VERSION 5.7 ;
  NOWIREEXTENSIONATPIN ON ;
  DIVIDERCHAR "/" ;
  BUSBITCHARS "[]" ;
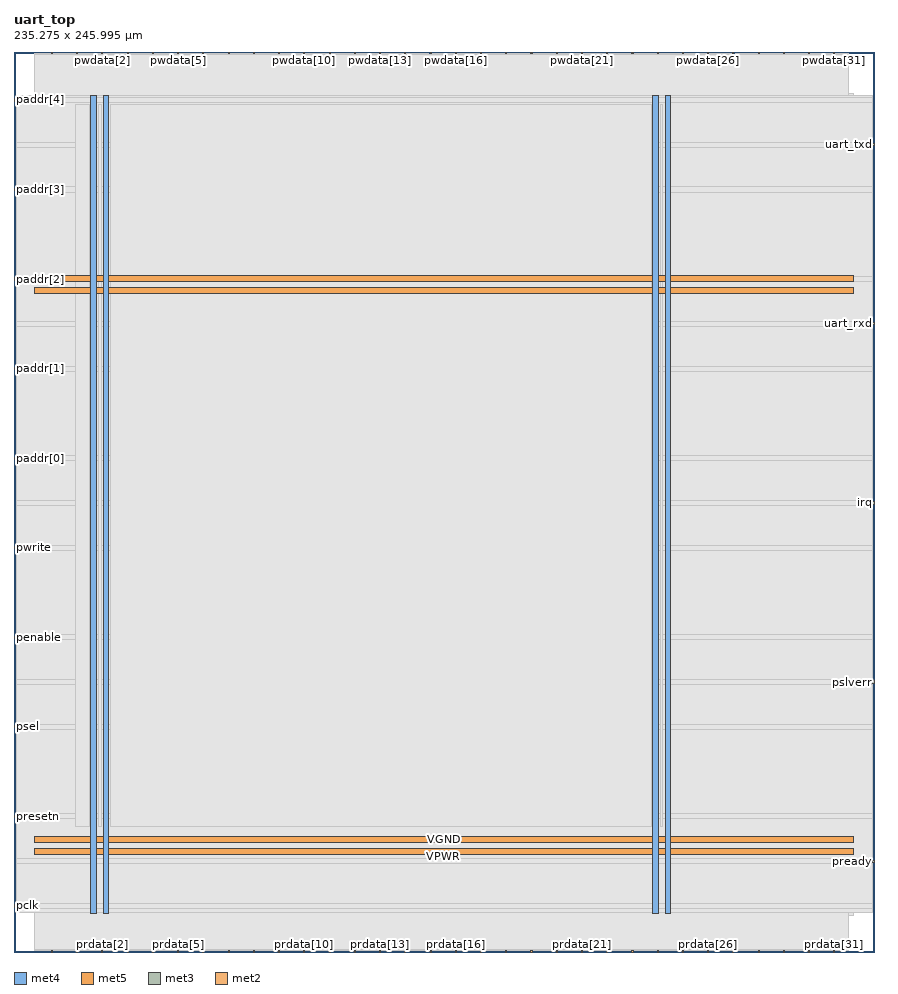
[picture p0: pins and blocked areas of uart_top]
MACRO uart_top
  CLASS BLOCK ;
  FOREIGN uart_top ;
  ORIGIN 0.000 0.000 ;
  SIZE 235.275 BY 245.995 ;
  PIN VGND
    DIRECTION INOUT ;
    USE GROUND ;
    PORT
      LAYER met4 ;
        RECT 24.340 10.640 25.940 234.160 ;
    END
    PORT
      LAYER met4 ;
        RECT 177.940 10.640 179.540 234.160 ;
    END
    PORT
      LAYER met5 ;
        RECT 5.520 30.030 229.540 31.630 ;
    END
    PORT
      LAYER met5 ;
        RECT 5.520 183.210 229.540 184.810 ;
    END
  END VGND
  PIN VPWR
    DIRECTION INOUT ;
    USE POWER ;
    PORT
      LAYER met4 ;
        RECT 21.040 10.640 22.640 234.160 ;
    END
    PORT
      LAYER met4 ;
        RECT 174.640 10.640 176.240 234.160 ;
    END
    PORT
      LAYER met5 ;
        RECT 5.520 26.730 229.540 28.330 ;
    END
    PORT
      LAYER met5 ;
        RECT 5.520 179.910 229.540 181.510 ;
    END
  END VPWR
  PIN irq
    DIRECTION OUTPUT ;
    USE SIGNAL ;
    ANTENNADIFFAREA 0.702900 ;
    PORT
      LAYER met3 ;
        RECT 234.675 122.440 235.275 123.040 ;
    END
  END irq
  PIN paddr[0]
    DIRECTION INPUT ;
    USE SIGNAL ;
    PORT
      LAYER met3 ;
        RECT 0.000 134.680 0.600 135.280 ;
    END
  END paddr[0]
  PIN paddr[1]
    DIRECTION INPUT ;
    USE SIGNAL ;
    PORT
      LAYER met3 ;
        RECT 0.000 159.160 0.600 159.760 ;
    END
  END paddr[1]
  PIN paddr[2]
    DIRECTION INPUT ;
    USE SIGNAL ;
    ANTENNAGATEAREA 0.647700 ;
    ANTENNADIFFAREA 0.434700 ;
    PORT
      LAYER met3 ;
        RECT 0.000 183.640 0.600 184.240 ;
    END
  END paddr[2]
  PIN paddr[3]
    DIRECTION INPUT ;
    USE SIGNAL ;
    ANTENNAGATEAREA 0.647700 ;
    ANTENNADIFFAREA 0.434700 ;
    PORT
      LAYER met3 ;
        RECT 0.000 208.120 0.600 208.720 ;
    END
  END paddr[3]
  PIN paddr[4]
    DIRECTION INPUT ;
    USE SIGNAL ;
    ANTENNAGATEAREA 0.647700 ;
    ANTENNADIFFAREA 0.434700 ;
    PORT
      LAYER met3 ;
        RECT 0.000 232.600 0.600 233.200 ;
    END
  END paddr[4]
  PIN pclk
    DIRECTION INPUT ;
    USE SIGNAL ;
    ANTENNAGATEAREA 1.286700 ;
    ANTENNADIFFAREA 0.434700 ;
    PORT
      LAYER met3 ;
        RECT 0.000 12.280 0.600 12.880 ;
    END
  END pclk
  PIN penable
    DIRECTION INPUT ;
    USE SIGNAL ;
    ANTENNAGATEAREA 0.647700 ;
    ANTENNADIFFAREA 0.434700 ;
    PORT
      LAYER met3 ;
        RECT 0.000 85.720 0.600 86.320 ;
    END
  END penable
  PIN prdata[0]
    DIRECTION OUTPUT ;
    USE SIGNAL ;
    ANTENNADIFFAREA 0.702900 ;
    PORT
      LAYER met2 ;
        RECT 10.210 0.000 10.490 0.280 ;
    END
  END prdata[0]
  PIN prdata[10]
    DIRECTION OUTPUT ;
    USE SIGNAL ;
    ANTENNADIFFAREA 0.702900 ;
    PORT
      LAYER met2 ;
        RECT 79.210 0.000 79.490 0.280 ;
    END
  END prdata[10]
  PIN prdata[11]
    DIRECTION OUTPUT ;
    USE SIGNAL ;
    ANTENNADIFFAREA 0.702900 ;
    PORT
      LAYER met2 ;
        RECT 86.110 0.000 86.390 0.280 ;
    END
  END prdata[11]
  PIN prdata[12]
    DIRECTION OUTPUT ;
    USE SIGNAL ;
    ANTENNADIFFAREA 0.702900 ;
    PORT
      LAYER met2 ;
        RECT 93.010 0.000 93.290 0.280 ;
    END
  END prdata[12]
  PIN prdata[13]
    DIRECTION OUTPUT ;
    USE SIGNAL ;
    ANTENNADIFFAREA 0.702900 ;
    PORT
      LAYER met2 ;
        RECT 99.910 0.000 100.190 0.280 ;
    END
  END prdata[13]
  PIN prdata[14]
    DIRECTION OUTPUT ;
    USE SIGNAL ;
    ANTENNADIFFAREA 0.702900 ;
    PORT
      LAYER met2 ;
        RECT 106.810 0.000 107.090 0.280 ;
    END
  END prdata[14]
  PIN prdata[15]
    DIRECTION OUTPUT ;
    USE SIGNAL ;
    ANTENNADIFFAREA 0.702900 ;
    PORT
      LAYER met2 ;
        RECT 113.710 0.000 113.990 0.280 ;
    END
  END prdata[15]
  PIN prdata[16]
    DIRECTION OUTPUT ;
    USE SIGNAL ;
    ANTENNADIFFAREA 0.702900 ;
    PORT
      LAYER met2 ;
        RECT 120.610 0.000 120.890 0.280 ;
    END
  END prdata[16]
  PIN prdata[17]
    DIRECTION OUTPUT ;
    USE SIGNAL ;
    ANTENNADIFFAREA 0.702900 ;
    PORT
      LAYER met2 ;
        RECT 127.510 0.000 127.790 0.280 ;
    END
  END prdata[17]
  PIN prdata[18]
    DIRECTION OUTPUT ;
    USE SIGNAL ;
    ANTENNADIFFAREA 0.702900 ;
    PORT
      LAYER met2 ;
        RECT 134.410 0.000 134.690 0.280 ;
    END
  END prdata[18]
  PIN prdata[19]
    DIRECTION OUTPUT ;
    USE SIGNAL ;
    ANTENNADIFFAREA 0.702900 ;
    PORT
      LAYER met2 ;
        RECT 141.310 0.000 141.590 0.280 ;
    END
  END prdata[19]
  PIN prdata[1]
    DIRECTION OUTPUT ;
    USE SIGNAL ;
    ANTENNADIFFAREA 0.702900 ;
    PORT
      LAYER met2 ;
        RECT 17.110 0.000 17.390 0.280 ;
    END
  END prdata[1]
  PIN prdata[20]
    DIRECTION OUTPUT ;
    USE SIGNAL ;
    ANTENNADIFFAREA 0.702900 ;
    PORT
      LAYER met2 ;
        RECT 148.210 0.000 148.490 0.280 ;
    END
  END prdata[20]
  PIN prdata[21]
    DIRECTION OUTPUT ;
    USE SIGNAL ;
    PORT
      LAYER met2 ;
        RECT 155.110 0.000 155.390 0.280 ;
    END
  END prdata[21]
  PIN prdata[22]
    DIRECTION OUTPUT ;
    USE SIGNAL ;
    PORT
      LAYER met2 ;
        RECT 162.010 0.000 162.290 0.280 ;
    END
  END prdata[22]
  PIN prdata[23]
    DIRECTION OUTPUT ;
    USE SIGNAL ;
    PORT
      LAYER met2 ;
        RECT 168.910 0.000 169.190 0.280 ;
    END
  END prdata[23]
  PIN prdata[24]
    DIRECTION OUTPUT ;
    USE SIGNAL ;
    PORT
      LAYER met2 ;
        RECT 175.810 0.000 176.090 0.280 ;
    END
  END prdata[24]
  PIN prdata[25]
    DIRECTION OUTPUT ;
    USE SIGNAL ;
    PORT
      LAYER met2 ;
        RECT 182.710 0.000 182.990 0.280 ;
    END
  END prdata[25]
  PIN prdata[26]
    DIRECTION OUTPUT ;
    USE SIGNAL ;
    PORT
      LAYER met2 ;
        RECT 189.610 0.000 189.890 0.280 ;
    END
  END prdata[26]
  PIN prdata[27]
    DIRECTION OUTPUT ;
    USE SIGNAL ;
    PORT
      LAYER met2 ;
        RECT 196.510 0.000 196.790 0.280 ;
    END
  END prdata[27]
  PIN prdata[28]
    DIRECTION OUTPUT ;
    USE SIGNAL ;
    PORT
      LAYER met2 ;
        RECT 203.410 0.000 203.690 0.280 ;
    END
  END prdata[28]
  PIN prdata[29]
    DIRECTION OUTPUT ;
    USE SIGNAL ;
    PORT
      LAYER met2 ;
        RECT 210.310 0.000 210.590 0.280 ;
    END
  END prdata[29]
  PIN prdata[2]
    DIRECTION OUTPUT ;
    USE SIGNAL ;
    ANTENNADIFFAREA 0.702900 ;
    PORT
      LAYER met2 ;
        RECT 24.010 0.000 24.290 0.280 ;
    END
  END prdata[2]
  PIN prdata[30]
    DIRECTION OUTPUT ;
    USE SIGNAL ;
    PORT
      LAYER met2 ;
        RECT 217.210 0.000 217.490 0.280 ;
    END
  END prdata[30]
  PIN prdata[31]
    DIRECTION OUTPUT ;
    USE SIGNAL ;
    PORT
      LAYER met2 ;
        RECT 224.110 0.000 224.390 0.280 ;
    END
  END prdata[31]
  PIN prdata[3]
    DIRECTION OUTPUT ;
    USE SIGNAL ;
    ANTENNADIFFAREA 0.702900 ;
    PORT
      LAYER met2 ;
        RECT 30.910 0.000 31.190 0.280 ;
    END
  END prdata[3]
  PIN prdata[4]
    DIRECTION OUTPUT ;
    USE SIGNAL ;
    ANTENNADIFFAREA 0.702900 ;
    PORT
      LAYER met2 ;
        RECT 37.810 0.000 38.090 0.280 ;
    END
  END prdata[4]
  PIN prdata[5]
    DIRECTION OUTPUT ;
    USE SIGNAL ;
    ANTENNADIFFAREA 0.702900 ;
    PORT
      LAYER met2 ;
        RECT 44.710 0.000 44.990 0.280 ;
    END
  END prdata[5]
  PIN prdata[6]
    DIRECTION OUTPUT ;
    USE SIGNAL ;
    ANTENNADIFFAREA 0.702900 ;
    PORT
      LAYER met2 ;
        RECT 51.610 0.000 51.890 0.280 ;
    END
  END prdata[6]
  PIN prdata[7]
    DIRECTION OUTPUT ;
    USE SIGNAL ;
    ANTENNADIFFAREA 0.702900 ;
    PORT
      LAYER met2 ;
        RECT 58.510 0.000 58.790 0.280 ;
    END
  END prdata[7]
  PIN prdata[8]
    DIRECTION OUTPUT ;
    USE SIGNAL ;
    ANTENNADIFFAREA 0.702900 ;
    PORT
      LAYER met2 ;
        RECT 65.410 0.000 65.690 0.280 ;
    END
  END prdata[8]
  PIN prdata[9]
    DIRECTION OUTPUT ;
    USE SIGNAL ;
    ANTENNADIFFAREA 0.702900 ;
    PORT
      LAYER met2 ;
        RECT 72.310 0.000 72.590 0.280 ;
    END
  END prdata[9]
  PIN pready
    DIRECTION OUTPUT ;
    USE SIGNAL ;
    PORT
      LAYER met3 ;
        RECT 234.675 24.520 235.275 25.120 ;
    END
  END pready
  PIN presetn
    DIRECTION INPUT ;
    USE SIGNAL ;
    ANTENNAGATEAREA 1.177200 ;
    ANTENNADIFFAREA 0.434700 ;
    PORT
      LAYER met3 ;
        RECT 0.000 36.760 0.600 37.360 ;
    END
  END presetn
  PIN psel
    DIRECTION INPUT ;
    USE SIGNAL ;
    ANTENNAGATEAREA 0.647700 ;
    ANTENNADIFFAREA 0.434700 ;
    PORT
      LAYER met3 ;
        RECT 0.000 61.240 0.600 61.840 ;
    END
  END psel
  PIN pslverr
    DIRECTION OUTPUT ;
    USE SIGNAL ;
    ANTENNADIFFAREA 0.702900 ;
    PORT
      LAYER met3 ;
        RECT 234.675 73.480 235.275 74.080 ;
    END
  END pslverr
  PIN pwdata[0]
    DIRECTION INPUT ;
    USE SIGNAL ;
    ANTENNAGATEAREA 0.647700 ;
    ANTENNADIFFAREA 0.434700 ;
    PORT
      LAYER met2 ;
        RECT 10.210 245.715 10.490 245.995 ;
    END
  END pwdata[0]
  PIN pwdata[10]
    DIRECTION INPUT ;
    USE SIGNAL ;
    ANTENNAGATEAREA 0.647700 ;
    ANTENNADIFFAREA 0.434700 ;
    PORT
      LAYER met2 ;
        RECT 79.210 245.715 79.490 245.995 ;
    END
  END pwdata[10]
  PIN pwdata[11]
    DIRECTION INPUT ;
    USE SIGNAL ;
    ANTENNAGATEAREA 0.647700 ;
    ANTENNADIFFAREA 0.434700 ;
    PORT
      LAYER met2 ;
        RECT 86.110 245.715 86.390 245.995 ;
    END
  END pwdata[11]
  PIN pwdata[12]
    DIRECTION INPUT ;
    USE SIGNAL ;
    ANTENNAGATEAREA 0.647700 ;
    ANTENNADIFFAREA 0.434700 ;
    PORT
      LAYER met2 ;
        RECT 93.010 245.715 93.290 245.995 ;
    END
  END pwdata[12]
  PIN pwdata[13]
    DIRECTION INPUT ;
    USE SIGNAL ;
    ANTENNAGATEAREA 0.647700 ;
    ANTENNADIFFAREA 0.434700 ;
    PORT
      LAYER met2 ;
        RECT 99.910 245.715 100.190 245.995 ;
    END
  END pwdata[13]
  PIN pwdata[14]
    DIRECTION INPUT ;
    USE SIGNAL ;
    ANTENNAGATEAREA 0.647700 ;
    ANTENNADIFFAREA 0.434700 ;
    PORT
      LAYER met2 ;
        RECT 106.810 245.715 107.090 245.995 ;
    END
  END pwdata[14]
  PIN pwdata[15]
    DIRECTION INPUT ;
    USE SIGNAL ;
    ANTENNAGATEAREA 0.647700 ;
    ANTENNADIFFAREA 0.434700 ;
    PORT
      LAYER met2 ;
        RECT 113.710 245.715 113.990 245.995 ;
    END
  END pwdata[15]
  PIN pwdata[16]
    DIRECTION INPUT ;
    USE SIGNAL ;
    PORT
      LAYER met2 ;
        RECT 120.610 245.715 120.890 245.995 ;
    END
  END pwdata[16]
  PIN pwdata[17]
    DIRECTION INPUT ;
    USE SIGNAL ;
    PORT
      LAYER met2 ;
        RECT 127.510 245.715 127.790 245.995 ;
    END
  END pwdata[17]
  PIN pwdata[18]
    DIRECTION INPUT ;
    USE SIGNAL ;
    PORT
      LAYER met2 ;
        RECT 134.410 245.715 134.690 245.995 ;
    END
  END pwdata[18]
  PIN pwdata[19]
    DIRECTION INPUT ;
    USE SIGNAL ;
    PORT
      LAYER met2 ;
        RECT 141.310 245.715 141.590 245.995 ;
    END
  END pwdata[19]
  PIN pwdata[1]
    DIRECTION INPUT ;
    USE SIGNAL ;
    ANTENNAGATEAREA 0.647700 ;
    ANTENNADIFFAREA 0.434700 ;
    PORT
      LAYER met2 ;
        RECT 17.110 245.715 17.390 245.995 ;
    END
  END pwdata[1]
  PIN pwdata[20]
    DIRECTION INPUT ;
    USE SIGNAL ;
    PORT
      LAYER met2 ;
        RECT 148.210 245.715 148.490 245.995 ;
    END
  END pwdata[20]
  PIN pwdata[21]
    DIRECTION INPUT ;
    USE SIGNAL ;
    PORT
      LAYER met2 ;
        RECT 155.110 245.715 155.390 245.995 ;
    END
  END pwdata[21]
  PIN pwdata[22]
    DIRECTION INPUT ;
    USE SIGNAL ;
    PORT
      LAYER met2 ;
        RECT 162.010 245.715 162.290 245.995 ;
    END
  END pwdata[22]
  PIN pwdata[23]
    DIRECTION INPUT ;
    USE SIGNAL ;
    PORT
      LAYER met2 ;
        RECT 168.910 245.715 169.190 245.995 ;
    END
  END pwdata[23]
  PIN pwdata[24]
    DIRECTION INPUT ;
    USE SIGNAL ;
    PORT
      LAYER met2 ;
        RECT 175.810 245.715 176.090 245.995 ;
    END
  END pwdata[24]
  PIN pwdata[25]
    DIRECTION INPUT ;
    USE SIGNAL ;
    PORT
      LAYER met2 ;
        RECT 182.710 245.715 182.990 245.995 ;
    END
  END pwdata[25]
  PIN pwdata[26]
    DIRECTION INPUT ;
    USE SIGNAL ;
    PORT
      LAYER met2 ;
        RECT 189.610 245.715 189.890 245.995 ;
    END
  END pwdata[26]
  PIN pwdata[27]
    DIRECTION INPUT ;
    USE SIGNAL ;
    PORT
      LAYER met2 ;
        RECT 196.510 245.715 196.790 245.995 ;
    END
  END pwdata[27]
  PIN pwdata[28]
    DIRECTION INPUT ;
    USE SIGNAL ;
    PORT
      LAYER met2 ;
        RECT 203.410 245.715 203.690 245.995 ;
    END
  END pwdata[28]
  PIN pwdata[29]
    DIRECTION INPUT ;
    USE SIGNAL ;
    PORT
      LAYER met2 ;
        RECT 210.310 245.715 210.590 245.995 ;
    END
  END pwdata[29]
  PIN pwdata[2]
    DIRECTION INPUT ;
    USE SIGNAL ;
    ANTENNAGATEAREA 0.647700 ;
    ANTENNADIFFAREA 0.434700 ;
    PORT
      LAYER met2 ;
        RECT 24.010 245.715 24.290 245.995 ;
    END
  END pwdata[2]
  PIN pwdata[30]
    DIRECTION INPUT ;
    USE SIGNAL ;
    PORT
      LAYER met2 ;
        RECT 217.210 245.715 217.490 245.995 ;
    END
  END pwdata[30]
  PIN pwdata[31]
    DIRECTION INPUT ;
    USE SIGNAL ;
    PORT
      LAYER met2 ;
        RECT 224.110 245.715 224.390 245.995 ;
    END
  END pwdata[31]
  PIN pwdata[3]
    DIRECTION INPUT ;
    USE SIGNAL ;
    ANTENNAGATEAREA 0.647700 ;
    ANTENNADIFFAREA 0.434700 ;
    PORT
      LAYER met2 ;
        RECT 30.910 245.715 31.190 245.995 ;
    END
  END pwdata[3]
  PIN pwdata[4]
    DIRECTION INPUT ;
    USE SIGNAL ;
    ANTENNAGATEAREA 0.631200 ;
    ANTENNADIFFAREA 0.434700 ;
    PORT
      LAYER met2 ;
        RECT 37.810 245.715 38.090 245.995 ;
    END
  END pwdata[4]
  PIN pwdata[5]
    DIRECTION INPUT ;
    USE SIGNAL ;
    ANTENNAGATEAREA 0.631200 ;
    ANTENNADIFFAREA 0.434700 ;
    PORT
      LAYER met2 ;
        RECT 44.710 245.715 44.990 245.995 ;
    END
  END pwdata[5]
  PIN pwdata[6]
    DIRECTION INPUT ;
    USE SIGNAL ;
    ANTENNAGATEAREA 0.647700 ;
    ANTENNADIFFAREA 0.434700 ;
    PORT
      LAYER met2 ;
        RECT 51.610 245.715 51.890 245.995 ;
    END
  END pwdata[6]
  PIN pwdata[7]
    DIRECTION INPUT ;
    USE SIGNAL ;
    ANTENNAGATEAREA 0.647700 ;
    ANTENNADIFFAREA 0.434700 ;
    PORT
      LAYER met2 ;
        RECT 58.510 245.715 58.790 245.995 ;
    END
  END pwdata[7]
  PIN pwdata[8]
    DIRECTION INPUT ;
    USE SIGNAL ;
    ANTENNAGATEAREA 0.647700 ;
    ANTENNADIFFAREA 0.434700 ;
    PORT
      LAYER met2 ;
        RECT 65.410 245.715 65.690 245.995 ;
    END
  END pwdata[8]
  PIN pwdata[9]
    DIRECTION INPUT ;
    USE SIGNAL ;
    ANTENNAGATEAREA 0.647700 ;
    ANTENNADIFFAREA 0.434700 ;
    PORT
      LAYER met2 ;
        RECT 72.310 245.715 72.590 245.995 ;
    END
  END pwdata[9]
  PIN pwrite
    DIRECTION INPUT ;
    USE SIGNAL ;
    ANTENNAGATEAREA 0.647700 ;
    ANTENNADIFFAREA 0.434700 ;
    PORT
      LAYER met3 ;
        RECT 0.000 110.200 0.600 110.800 ;
    END
  END pwrite
  PIN uart_rxd
    DIRECTION INPUT ;
    USE SIGNAL ;
    ANTENNAGATEAREA 0.647700 ;
    ANTENNADIFFAREA 0.434700 ;
    PORT
      LAYER met3 ;
        RECT 234.675 171.400 235.275 172.000 ;
    END
  END uart_rxd
  PIN uart_txd
    DIRECTION OUTPUT ;
    USE SIGNAL ;
    ANTENNADIFFAREA 0.702900 ;
    PORT
      LAYER met3 ;
        RECT 234.675 220.360 235.275 220.960 ;
    END
  END uart_txd
  OBS
      LAYER nwell ;
        RECT 5.330 10.795 229.730 234.005 ;
      LAYER li1 ;
        RECT 5.520 10.795 229.540 234.005 ;
      LAYER met1 ;
        RECT 5.520 9.900 229.540 234.560 ;
      LAYER met2 ;
        RECT 5.610 245.435 9.930 245.715 ;
        RECT 10.770 245.435 16.830 245.715 ;
        RECT 17.670 245.435 23.730 245.715 ;
        RECT 24.570 245.435 30.630 245.715 ;
        RECT 31.470 245.435 37.530 245.715 ;
        RECT 38.370 245.435 44.430 245.715 ;
        RECT 45.270 245.435 51.330 245.715 ;
        RECT 52.170 245.435 58.230 245.715 ;
        RECT 59.070 245.435 65.130 245.715 ;
        RECT 65.970 245.435 72.030 245.715 ;
        RECT 72.870 245.435 78.930 245.715 ;
        RECT 79.770 245.435 85.830 245.715 ;
        RECT 86.670 245.435 92.730 245.715 ;
        RECT 93.570 245.435 99.630 245.715 ;
        RECT 100.470 245.435 106.530 245.715 ;
        RECT 107.370 245.435 113.430 245.715 ;
        RECT 114.270 245.435 120.330 245.715 ;
        RECT 121.170 245.435 127.230 245.715 ;
        RECT 128.070 245.435 134.130 245.715 ;
        RECT 134.970 245.435 141.030 245.715 ;
        RECT 141.870 245.435 147.930 245.715 ;
        RECT 148.770 245.435 154.830 245.715 ;
        RECT 155.670 245.435 161.730 245.715 ;
        RECT 162.570 245.435 168.630 245.715 ;
        RECT 169.470 245.435 175.530 245.715 ;
        RECT 176.370 245.435 182.430 245.715 ;
        RECT 183.270 245.435 189.330 245.715 ;
        RECT 190.170 245.435 196.230 245.715 ;
        RECT 197.070 245.435 203.130 245.715 ;
        RECT 203.970 245.435 210.030 245.715 ;
        RECT 210.870 245.435 216.930 245.715 ;
        RECT 217.770 245.435 223.830 245.715 ;
        RECT 224.670 245.435 228.070 245.715 ;
        RECT 5.610 0.560 228.070 245.435 ;
        RECT 5.610 0.280 9.930 0.560 ;
        RECT 10.770 0.280 16.830 0.560 ;
        RECT 17.670 0.280 23.730 0.560 ;
        RECT 24.570 0.280 30.630 0.560 ;
        RECT 31.470 0.280 37.530 0.560 ;
        RECT 38.370 0.280 44.430 0.560 ;
        RECT 45.270 0.280 51.330 0.560 ;
        RECT 52.170 0.280 58.230 0.560 ;
        RECT 59.070 0.280 65.130 0.560 ;
        RECT 65.970 0.280 72.030 0.560 ;
        RECT 72.870 0.280 78.930 0.560 ;
        RECT 79.770 0.280 85.830 0.560 ;
        RECT 86.670 0.280 92.730 0.560 ;
        RECT 93.570 0.280 99.630 0.560 ;
        RECT 100.470 0.280 106.530 0.560 ;
        RECT 107.370 0.280 113.430 0.560 ;
        RECT 114.270 0.280 120.330 0.560 ;
        RECT 121.170 0.280 127.230 0.560 ;
        RECT 128.070 0.280 134.130 0.560 ;
        RECT 134.970 0.280 141.030 0.560 ;
        RECT 141.870 0.280 147.930 0.560 ;
        RECT 148.770 0.280 154.830 0.560 ;
        RECT 155.670 0.280 161.730 0.560 ;
        RECT 162.570 0.280 168.630 0.560 ;
        RECT 169.470 0.280 175.530 0.560 ;
        RECT 176.370 0.280 182.430 0.560 ;
        RECT 183.270 0.280 189.330 0.560 ;
        RECT 190.170 0.280 196.230 0.560 ;
        RECT 197.070 0.280 203.130 0.560 ;
        RECT 203.970 0.280 210.030 0.560 ;
        RECT 210.870 0.280 216.930 0.560 ;
        RECT 217.770 0.280 223.830 0.560 ;
        RECT 224.670 0.280 228.070 0.560 ;
      LAYER met3 ;
        RECT 0.600 233.600 234.675 234.085 ;
        RECT 1.000 232.200 234.675 233.600 ;
        RECT 0.600 221.360 234.675 232.200 ;
        RECT 0.600 219.960 234.275 221.360 ;
        RECT 0.600 209.120 234.675 219.960 ;
        RECT 1.000 207.720 234.675 209.120 ;
        RECT 0.600 184.640 234.675 207.720 ;
        RECT 1.000 183.240 234.675 184.640 ;
        RECT 0.600 172.400 234.675 183.240 ;
        RECT 0.600 171.000 234.275 172.400 ;
        RECT 0.600 160.160 234.675 171.000 ;
        RECT 1.000 158.760 234.675 160.160 ;
        RECT 0.600 135.680 234.675 158.760 ;
        RECT 1.000 134.280 234.675 135.680 ;
        RECT 0.600 123.440 234.675 134.280 ;
        RECT 0.600 122.040 234.275 123.440 ;
        RECT 0.600 111.200 234.675 122.040 ;
        RECT 1.000 109.800 234.675 111.200 ;
        RECT 0.600 86.720 234.675 109.800 ;
        RECT 1.000 85.320 234.675 86.720 ;
        RECT 0.600 74.480 234.675 85.320 ;
        RECT 0.600 73.080 234.275 74.480 ;
        RECT 0.600 62.240 234.675 73.080 ;
        RECT 1.000 60.840 234.675 62.240 ;
        RECT 0.600 37.760 234.675 60.840 ;
        RECT 1.000 36.360 234.675 37.760 ;
        RECT 0.600 25.520 234.675 36.360 ;
        RECT 0.600 24.120 234.275 25.520 ;
        RECT 0.600 13.280 234.675 24.120 ;
        RECT 1.000 11.880 234.675 13.280 ;
        RECT 0.600 10.715 234.675 11.880 ;
      LAYER met4 ;
        RECT 16.855 34.175 20.640 231.705 ;
        RECT 23.040 34.175 23.940 231.705 ;
        RECT 26.340 34.175 174.240 231.705 ;
        RECT 176.640 34.175 177.265 231.705 ;
  END
END uart_top
END LIBRARY

